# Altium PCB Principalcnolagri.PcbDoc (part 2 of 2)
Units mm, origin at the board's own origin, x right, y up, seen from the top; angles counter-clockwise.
Board outline 45.4 x 70.2 mm, 2 copper layers (Top Layer, Bottom Layer); 50 components, 70 nets, 241 pads, 57 vias.

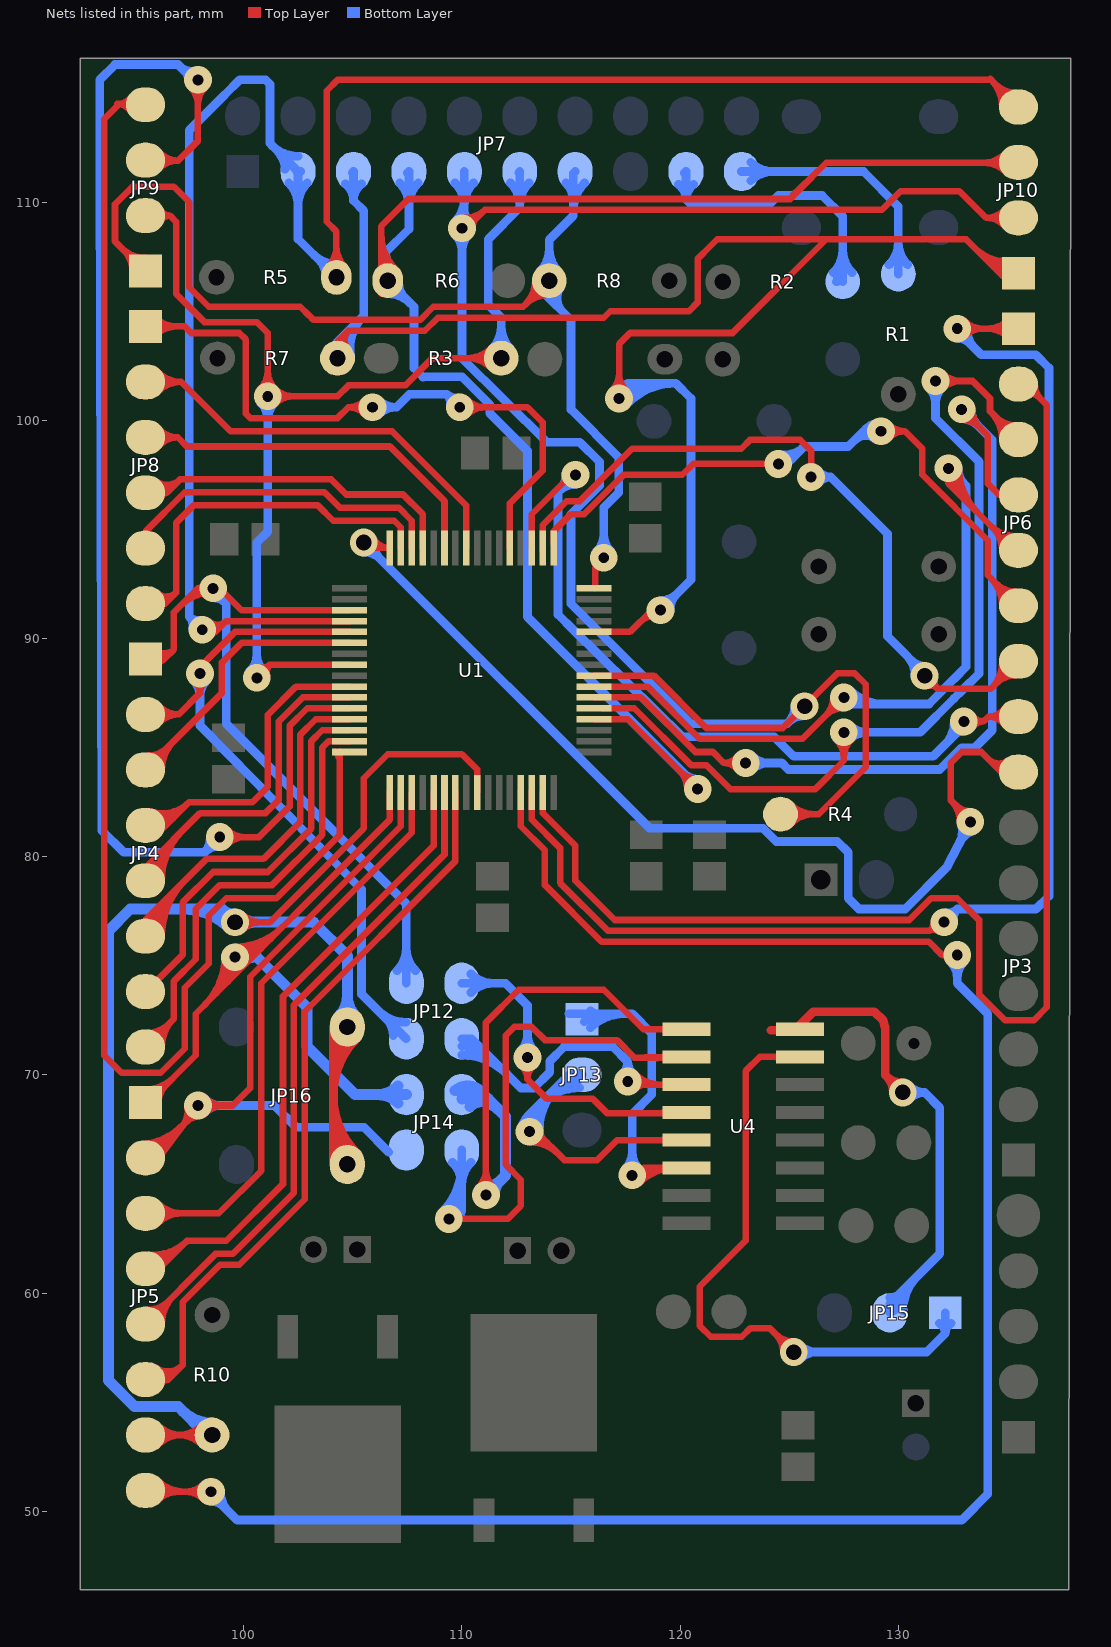
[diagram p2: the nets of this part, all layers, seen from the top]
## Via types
v1: diameter 1.27, hole 0.5, Top Layer to Bottom Layer, 46 vias
v2: diameter 1.27, hole 0.711, Top Layer to Bottom Layer, 10 vias
v3: diameter 1.524, hole 0.5, Top Layer to Bottom Layer, 1 vias

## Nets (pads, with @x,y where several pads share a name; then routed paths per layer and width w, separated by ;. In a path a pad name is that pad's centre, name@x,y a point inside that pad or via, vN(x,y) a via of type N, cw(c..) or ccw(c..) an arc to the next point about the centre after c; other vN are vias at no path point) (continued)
NetJP3_8: JP3.8 U1.16 | length 55.6
  Top Layer w0.3: v2(105.5,94.4) 105.1,94.6 105.55,94.15 U1.16@106.7,94.15 cw(c106.7,95.012) v2@105.932,94.62 ; v2@105.665,94.484 ccw(c106.21,94.762) 106.21,94.15 ; 132.401,82.599 cw(c131.403,81.6) v1@132.815,81.6 ; 132.643,82.357 ccw(c133.3,83.014) v1@133.3,82.085 ; v1(133.3,81.6) 133.3,81.7 132.4,82.6 132.4,84.3 132.9,84.8 133.8,84.8 134.72,83.88 JP3.8@135.5,83.88 ; 134.14,84.46 ccw(c134.609,84.929) JP3.8@135.009,84.399 ; 134.384,84.216 ccw(c134.819,84.651) JP3.8@135.189,84.16
  Bottom Layer w0.4: v2@105.5,93.965 cw(c105.5,92.915) 106.243,93.657 cw(c106.985,94.4) v2@105.935,94.4 ; v2(105.5,94.4) 118.6,81.3 123.8,81.3 124.4,80.7 127.2,80.7 127.7,80.2 127.7,78.1 128.2,77.6 130.3,77.6 132.2,79.5 v1(133.3,81.6) ; v1@132.885,81.47 cw(c131.882,81.157) 132.813,80.67 cw(c133.743,80.182) v1@133.43,81.185
NetJP4_1: JP4.1 JP12.1 U1.19 | length 46.5
  Top Layer w0.3: JP4.1@95.5,89.4 JP4.1@95.5,89.06 ; JP4.1@95.708,89.276 ccw(c96.142,89.726) 96.584,89.284 ; JP4.1@95.916,89.492 ccw(c96.354,89.946) 96.8,89.5 ; JP4.1@96.063,88.853 cw(c96.36,88.744) 96.36,89.06 ; JP4.1@96.063,89.267 ccw(c96.36,89.376) 96.36,89.06 ; 96.368,89.068 cw(c95.93,89.506) JP4.1@95.5,89.06 ; 97.089,91.489 cw(c98.6,89.978) v1@98.6,92.115 ; 97.55,91.95 cw(c97.907,91.593) v1@98.261,91.954 ; 97.601,92.001 cw(c98.6,91.003) v1@98.6,92.415 ; 97.764,92.164 cw(c98.119,91.809) v1@98.471,92.168 ; v1@98.146,92.13 ccw(c97.9,92.037) 97.9,92.3 ; v1@98.146,92.47 cw(c97.9,92.563) 97.9,92.3 ; v1@98.8,92 v1(98.6,92.3) 97.9,92.3 ; v1@98.9,92.3 99.9,91.3 U1.19@104.85,91.3 ; JP4.1@95.5,89.06 96.36,89.06 ; 96.36,89.06 96.8,89.5 ; 96.8,89.5 96.8,91.2 97.9,92.3
  Bottom Layer w0.4: v1(98.6,92.3) 99.2,91.6 ; v1@98.609,91.865 cw(c98.623,91.106) 99.2,91.6 ; v1@99.028,92.225 ccw(c99.777,92.094) 99.2,91.6 ; JP12.1@107.026,74.774 ccw(c106.001,75.799) 107.45,75.799 ccw(c108.899,75.799) JP12.1@107.874,74.774 ; JP12.1@107.45,74.2 107.45,77.85 99.2,86.1 99.2,91.6
NetJP4_2: JP4.2 JP12.3 U1.21 | length 39.9
  Top Layer w0.3: JP4.2@95.5,87 JP4.2@95.5,86.52 97.02,86.52 ; JP4.2@96.092,86.095 cw(c97.02,85.294) 97.02,86.52 ; JP4.2@96.092,86.945 ccw(c97.02,87.746) 97.02,86.52 ; v1@97.733,87.995 cw(c97.408,87.5) 98,87.5 ; v1@98.267,87.995 ccw(c98.592,87.5) 98,87.5 ; U1.21@104.85,90.3 99.6,90.3 98,88.7 98,87.5 ; 97.02,86.52 98,87.5
  Bottom Layer w0.4: v1@97.692,88.092 cw(c96.95,87.35) 98,87.35 cw(c99.05,87.35) v1@98.308,88.092 ; v1(98,88.4) 98,86 105.4,78.5 105.4,73.7 105.41,73.7 JP12.3@107.45,71.66 ; 106.17,72.94 ccw(c107.45,74.221) JP12.3@107.45,72.41 ; 106.532,72.578 cw(c105.764,71.81) JP12.3@106.85,71.81
NetJP4_3: JP4.3 U1.22 | length 16.3
  Top Layer w0.3: JP4.3@95.6,84.63 ccw(c95.6,85.91) 96.505,85.005 ; JP4.3@95.88,83.98 JP4.3@95.5,83.98 95.5,84 99,87.5 99,88.9 99.9,89.8 U1.22@104.85,89.8 ; JP4.3@95.95,83.98 cw(c97.085,83.98) 96.282,84.782 ; JP4.3@96.25,83.98 cw(c98.109,83.98) 96.794,85.294
NetJP4_4: JP4.4 U1.26 | length 20.2
  Top Layer w0.3: JP4.4@95.5,81.44 96.44,81.44 ; JP4.4@95.529,81.2 ccw(c95.787,82.072) 96.429,81.429 ; JP4.4@95.614,81.488 ccw(c95.949,82.623) 96.786,81.786 ; JP4.4@95.699,81.776 ccw(c96.112,83.174) 97.143,82.143 ; JP4.4@95.784,82.063 ccw(c96.275,83.725) 97.5,82.5 ; JP4.4@96.229,81.277 cw(c96.44,81.222) 96.44,81.44 ; JP4.4@96.229,81.603 ccw(c96.44,81.658) 96.44,81.44 ; U1.26@104.85,87.8 102.4,87.8 101.1,86.5 101.1,83.2 100.4,82.5 97.5,82.5 ; 96.44,81.44 97.5,82.5
NetJP4_5: JP4.5 U1.27 | length 21.5
  Top Layer w0.3: JP4.5@95.65,78.9 cw(c97.461,78.9) 96.18,80.18 ; JP4.5@95.7,78.9 JP4.5@95.5,78.9 95.5,79.5 98,82 101,82 101.6,82.6 101.6,86.2 102.7,87.3 U1.27@104.85,87.3 ; JP4.5@95.95,78.9 cw(c98.485,78.9) 96.692,80.692 ; JP4.5@96.25,78.9 cw(c99.509,78.9) 97.205,81.205
NetJP4_6: JP4.6 U1.29 | length 24.1
  Top Layer w0.3: JP4.6@95.35,76.36 cw(c96.774,76.36) 95.767,77.367 ; JP4.6@95.5,76.36 95.5,77.1 98.3,79.9 100.9,79.9 102.6,81.6 102.6,85.6 103.3,86.3 U1.29@104.85,86.3 ; JP4.6@95.65,76.36 cw(c97.799,76.36) 96.279,77.879 ; JP4.6@95.95,76.36 cw(c98.823,76.36) 96.791,78.391 ; JP4.6@96.25,76.36 cw(c99.847,76.36) 97.304,78.904
NetJP4_7: JP4.7 U1.30 | length 18.1
  Top Layer w0.3: JP4.7@95.5,73.82 95.52,73.82 97.2,75.5 97.2,77.9 98.6,79.3 101.1,79.3 103.1,81.3 103.1,85.3 103.6,85.8 U1.30@104.85,85.8
NetJP4_8: JP4.8 U1.31 | length 23.2
  Top Layer w0.3: JP4.8@95.5,71.28 96.8,72.58 96.8,74.3 97.8,75.3 97.8,77.6 98.9,78.7 101.3,78.7 103.6,81 103.6,85 103.9,85.3 U1.31@104.85,85.3 ; JP4.8@95.6,71.93 ccw(c95.6,73.258) 96.539,72.319 ; JP4.8@95.95,71.28 cw(c97.036,71.28) 96.268,72.048 ; JP4.8@96.25,71.28 cw(c98.061,71.28) 96.78,72.56
NetJP5_1: JP5.1 JP14.1 U1.33 | length 49.9
  Top Layer w0.3: JP5.1@95.5,68.74 95.64,68.74 97.8,70.9 97.8,72.8 106.686,81.686 106.7,81.686 U1.33@106.7,82.95 ; JP5.1@95.5,69.04 ccw(c95.5,70.102) 96.251,69.351 ; JP5.1@95.5,69.34 ccw(c95.5,71.127) 96.763,69.863 ; JP5.1@96.1,68.74 cw(c97.21,68.74) 96.425,69.525 ; 98.206,73.206 ccw(c96.013,75.4) v1@99.115,75.4 ; 98.718,73.719 ccw(c97.037,75.4) v1@99.415,75.4 ; 99.231,74.231 ccw(c98.061,75.4) v1@99.715,75.4 ; v1@99.6,74.985 ccw(c99.6,75.914) 100.257,75.257 ; v1@99.6,75.285 ccw(c99.6,76.939) 100.769,75.769 ; v1@99.6,75.585 ccw(c99.6,77.963) 101.281,76.282 ; v1@99.6,75.885 ccw(c99.6,78.987) 101.794,76.794 ; 99.743,74.743 ccw(c99.086,75.4) v1@100.015,75.4
  Bottom Layer w0.5: v1@99.6,75.3 v1(99.6,75.4) 100.6,75.4 102.9,73.1 102.9,71.3 105.1,69.1 JP14.1@107.45,69.1 ; v1@99.872,75.128 cw(c100.529,74.471) 100.529,75.4 cw(c100.529,76.329) v1@99.872,75.672 ; JP14.1@107.061,68.711 ccw(c106.122,67.772) 106.122,69.1 ccw(c106.122,70.428) JP14.1@107.061,69.489
NetJP5_2: JP5.2 JP14.3 U1.34 | length 43
  Top Layer w0.3: JP5.2@95.5,66.2 96.1,66.2 v1(97.9,68.6) 99.5,68.6 100.3,69.4 100.3,74.5 107.2,81.4 107.2,82 U1.34@107.2,82.95 U1.34@107.2,83.025 ; JP5.2@95.508,66.843 ccw(c95.093,69.749) 97.441,67.988 ; JP5.2@95.55,66.547 ccw(c95.238,68.735) 97.006,67.409 ; JP5.2@95.593,66.25 ccw(c95.383,67.721) 96.572,66.829 ; v1@97.42,68.531 cw(c96.261,68.366) 97.197,67.663 cw(c98.134,66.961) v1@97.969,68.12 ; v1@98.243,68.257 cw(c99.071,67.429) 99.071,68.6 cw(c99.071,69.771) v1@98.243,68.943
  Bottom Layer w0.4: v1(97.9,68.6) 101.4,68.6 102.4,67.6 105.51,67.6 JP14.3@106.65,66.46 ; v1@98.208,68.292 cw(c98.95,67.55) 98.95,68.6 cw(c98.95,69.65) v1@98.208,68.908
NetJP5_3: JP5.3 U1.35 | length 30.1
  Top Layer w0.3: JP5.3@95.5,63.66 98.86,63.66 100.8,65.6 100.8,74.2 107.7,81.1 U1.35@107.7,82.925 ; JP5.3@95.847,63.413 cw(c96.445,62.815) 96.445,63.66 cw(c96.445,64.505) JP5.3@95.847,63.908 ; JP5.3@96.06,63.2 cw(c97.169,62.091) 97.169,63.66 cw(c97.169,65.229) JP5.3@96.06,64.12
NetJP5_4: JP5.4 U1.37 | length 33
  Top Layer w0.3: JP5.4@95.5,61.12 96.12,61.12 97.4,62.4 ; JP5.4@95.604,61.17 ccw(c95.703,62.281) 96.492,61.492 ; JP5.4@95.631,61.469 ccw(c95.778,63.114) 96.946,61.946 ; JP5.4@95.658,61.767 ccw(c95.852,63.948) 97.4,62.4 ; U1.37@108.7,82.95 108.7,80.5 101.8,73.6 101.8,65 99.2,62.4 97.4,62.4
NetJP5_5: JP5.5 U1.38 | length 35.7
  Top Layer w0.3: JP5.5@95.598,59.23 ccw(c95.594,60.557) 96.535,59.622 ; JP5.5@95.9,58.8 JP5.5@95.5,58.58 ; JP5.5@95.95,58.581 cw(c97.037,58.584) 96.266,59.351 ; JP5.5@96.08,58.58 JP5.5@95.5,58.58 ; JP5.5@96.25,58.582 cw(c98.061,58.588) 96.777,59.865 ; 109.2,82.109 U1.38@109.2,82.95 109.2,80.1 102.3,73.2 102.3,64.6 99.5,61.8 98.7,61.8 JP5.5@95.5,58.58
NetJP5_6: JP5.6 U1.39 | length 38.5
  Top Layer w0.3: JP5.6@95.5,56.04 96.54,56.04 ; JP5.6@95.628,56.082 ccw(c96.094,56.775) 96.684,56.184 ; JP5.6@95.795,56.331 ccw(c96.301,57.083) 96.942,56.442 ; JP5.6@95.962,56.58 ccw(c96.508,57.392) 97.2,56.7 ; JP5.6@96.208,55.811 cw(c96.54,55.685) 96.54,56.04 ; JP5.6@96.208,56.27 ccw(c96.54,56.395) 96.54,56.04 ; U1.39@109.7,82.95 109.7,79.8 102.8,72.9 102.8,64.3 99.8,61.3 98.919,61.3 97.2,59.581 97.2,56.7 ; 96.54,56.04 97.2,56.7
NetJP5_7: JP5.7 JP16.2 R10.2 U1.41 | length 100.7
  Top Layer w0.3: JP5.7@95.8,53.5 R10.2@98.5,53.5 ; JP5.7@95.847,53.253 cw(c96.445,52.655) 96.445,53.5 cw(c96.445,54.345) JP5.7@95.847,53.748 ; JP5.7@96.06,53.04 cw(c97.169,51.931) 97.169,53.5 cw(c97.169,55.069) JP5.7@96.06,53.96 ; R10.2@98.09,53.04 ccw(c96.981,51.931) 96.981,53.5 ccw(c96.981,55.069) R10.2@98.09,53.96 ; R10.2@98.303,53.253 ccw(c97.705,52.655) 97.705,53.5 ccw(c97.705,54.345) R10.2@98.303,53.747 ; v2(99.6,77) 101.2,77 105.5,81.3 105.5,83.6 106.6,84.7 110,84.7 110.7,84 U1.41@110.7,82.95 ; v2@99.943,76.657 cw(c100.771,75.829) 100.771,77 cw(c100.771,78.171) v2@99.943,77.343
  Top Layer w0.4: JP16.2@104.115,65.9 JP16.2@104.115,72.2 ; 104.115,67.05 ccw(c105.8,67.05) JP16.2@104.609,65.859 ; 104.115,68.016 ccw(c106.766,68.016) JP16.2@104.891,66.141 ; 104.115,68.982 ccw(c107.732,68.982) JP16.2@105.174,66.424 ; 104.115,69.118 cw(c107.732,69.118) JP16.2@105.174,71.676 ; 104.115,70.084 cw(c106.766,70.084) JP16.2@104.891,71.959 ; 104.115,71.05 cw(c105.8,71.05) JP16.2@104.609,72.241
  Bottom Layer w0.4: v2(99.6,77) 99.7,77.1 v2(99.6,77)
  Bottom Layer w0.5: 97.184,54.616 ccw(c98.55,55.981) R10.2@98.55,54.05 ; 97.222,77.6 cw(c97.222,74.622) v2@99.328,76.728 ; 97.788,54.012 cw(c97.276,53.5) R10.2@98,53.5 ; 98.429,77.6 cw(c98.429,75.829) v2@99.681,77.081 ; R10.2@98.55,53.5 98.3,53.5 97,54.8 95,54.8 93.8,56 93.8,76.6 94.8,77.6 99,77.6 ; v2@99.216,77.026 ccw(c98.475,77.075) 99,77.6 ; v2@99.574,77.384 cw(c99.525,78.125) 99,77.6 ; v2@99.872,76.728 cw(c100.529,76.071) 100.529,77 cw(c100.529,77.929) v2@99.872,77.272 ; JP16.2@104.361,72.689 ccw(c103.422,73.628) 104.75,73.628 ccw(c106.078,73.628) JP16.2@105.139,72.689 ; JP16.2@104.75,72.2 104.75,75.45 103.2,77 v2(99.6,77) 99,77.6
NetJP5_8: JP5.8 U1.45 | length 98.7
  Top Layer w0.3: JP5.8@95.8,50.9 v1(98.5,50.9) ; JP5.8@95.847,51.208 ccw(c96.59,51.95) 96.59,50.9 ; JP5.8@96.06,50.5 cw(c97.024,49.536) 97.024,50.9 ; JP5.8@96.06,51.42 ccw(c97.314,52.674) 97.314,50.9 ; v1@98.157,50.557 ccw(c97.329,49.729) 97.329,50.9 ccw(c97.329,52.071) v1@98.157,51.243 ; U1.45@112.7,83 112.7,81.4 113.8,80.3 113.8,78.7 116.4,76.1 131.4,76.1 132,75.5 ; v1@132.246,75.33 ccw(c132,75.237) 132,75.5 ; v1@132.246,75.67 cw(c132,75.763) 132,75.5 ; v1(132.7,75.5) 132,75.5
  Bottom Layer w0.4: v1@98.5,50.465 cw(c98.5,49.656) 99.072,50.228 ; v1(98.5,50.9) 98.5,50.8 99.7,49.6 132.9,49.6 134.1,50.8 134.1,72.8 132.7,74.2 v1(132.7,75.5) ; v1@98.935,50.9 ccw(c100.227,50.9) 99.313,49.987 ; v1@132.392,75.192 cw(c131.65,74.45) 132.7,74.45 cw(c133.75,74.45) v1@133.008,75.192
NetJP6_1: JP6.1 U1.46 | length 68.5
  Top Layer w0.3: U1.46@113.2,83 113.2,81.7 114.5,80.4 114.5,78.8 116.7,76.6 131.4,76.6 ; v1@131.615,76.985 cw(c131.188,76.971) 131.4,76.6 ; v1@131.841,76.59 ccw(c131.612,76.229) 131.4,76.6 ; v1(132.1,77) 131.4,76.6 ; v1(132.7,104.2) JP6.1@135.5,104.2 ; v1@133.043,103.857 cw(c133.871,103.029) 133.871,104.2 cw(c133.871,105.371) v1@133.043,104.543 ; JP6.1@135.076,103.776 ccw(c134.051,102.751) 134.051,104.2 ccw(c134.052,105.648) JP6.1@135.076,104.624
  Bottom Layer w0.4: v1(132.1,77) 132.7,77.6 ; v1@132.17,77.429 ccw(c132.269,78.031) 132.7,77.6 ; v1@132.529,77.07 cw(c133.131,77.169) 132.7,77.6 ; v1@132.7,103.765 cw(c132.7,102.956) 133.272,103.528 ; v1(132.7,104.2) 132.7,104.1 133.8,103 136.3,103 136.9,102.4 136.9,78.2 136.3,77.6 132.7,77.6 ; v1@133.135,104.2 ccw(c134.427,104.2) 133.513,103.287
NetJP6_2: JP6.2 U1.47 | length 63
  Top Layer w0.3: U1.47@113.7,82.95 113.7,82 115.2,80.5 115.2,78.9 117,77.1 130.5,77.1 131.5,78.1 132.7,78.1 133.7,77.1 133.7,73.7 134.9,72.5 136.2,72.5 136.8,73.1 136.8,100.7 135.8,101.7 JP6.2@135.5,101.66 ; JP6.2@135.64,101.312 cw(c135.757,100.295) 136.481,101.019 ; JP6.2@136.25,101.66 ccw(c137.24,101.66) 136.54,100.96
NetJP6_3: JP6.3 U1.53 | length 51.6
  Top Layer w0.3: U1.53@116.4,86.8 117.9,86.8 120.5,84.2 121.2,84.2 122.3,83.1 126.2,83.1 127.5,84.4 v1(127.5,85.7) ; v1@127.157,85.357 cw(c126.329,84.529) 127.5,84.529 cw(c128.671,84.529) v1@127.843,85.357 ; v1(131.7,101.8) 133.4,101.8 134.2,101 134.2,100.42 JP6.3@135.5,99.12 ; v1@132.043,101.457 cw(c132.871,100.629) 132.871,101.8 cw(c132.871,102.971) v1@132.043,102.143 ; 134.22,100.4 cw(c132.939,99.12) JP6.3@134.75,99.12 ; 134.461,100.159 ccw(c135.4,101.098) JP6.3@135.4,99.77 ; 134.732,99.888 cw(c133.964,99.12) JP6.3@135.05,99.12
  Bottom Layer w0.4: v1(127.5,85.7) 131,85.7 132.551,87.251 132.951,87.651 133.7,88.4 133.7,98.1 131.7,100.1 v1(131.7,101.8) ; v1@127.808,85.392 cw(c128.55,84.65) 128.55,85.7 cw(c128.55,86.75) v1@127.808,86.008 ; v1@131.392,101.492 cw(c130.65,100.75) 131.7,100.75 cw(c132.75,100.75) v1@132.008,101.492
NetJP6_4: JP6.4 U1.54 | length 48.2
  Top Layer w0.3: U1.54@116.05,87.3 118.2,87.3 120.7,84.8 121.5,84.8 122,84.3 ; v1@122.619,84 ccw(c122,83.512) 122,84.3 ; v1@122.619,84.6 cw(c122,85.088) 122,84.3 ; v1(123,84.3) 122,84.3 ; v1@132.9,100.015 cw(c132.9,98.844) 133.728,99.672 cw(c134.556,100.5) v1@133.385,100.5 ; v1(132.9,100.5) 134.1,99.3 134.1,97.1 134.62,96.58 JP6.4@135.5,96.58 JP6.4@135.5,97.1
  Bottom Layer w0.4: v1(123,84.3) 124.651,84.3 124.951,84 131.9,84 132.9,85 133.5,85 134.3,85.8 134.3,99.1 v1(132.9,100.5) ; v1@123.308,83.992 cw(c124.05,83.25) 124.05,84.3 cw(c124.05,85.35) v1@123.308,84.608 ; v1@132.9,100.065 cw(c132.9,99.015) 133.643,99.757 cw(c134.385,100.5) v1@133.335,100.5
NetJP6_5: JP6.5 U1.55 | length 49.7
  Top Layer w0.3: U1.55@116.05,87.8 118.5,87.8 120.9,85.4 125.6,85.4 v1(127.5,87.3) ; v1@127.015,87.3 cw(c125.844,87.3) 126.672,86.472 cw(c127.5,85.644) v1@127.5,86.815 ; v1@132.185,97.8 ccw(c133.597,97.8) 132.599,96.801 ; v1(132.3,97.8) 132.3,97.1 ; v1@132.485,97.8 ccw(c134.622,97.8) 133.111,96.289 ; v1@132.785,97.8 ccw(c135.646,97.8) 133.623,95.777 ; 134.222,95.178 ccw(c135.4,96.356) JP6.5@135.4,94.69 ; 134.319,95.081 cw(c133.277,94.04) JP6.5@134.75,94.04 ; 134.734,94.666 ccw(c135.4,95.331) JP6.5@135.4,94.39 ; JP6.5@135.5,94.04 135.2,94.2 134.9,94.5 132.3,97.1 ; 132.3,97.1 cw(c132.563,97.1) 132.47,97.346 ccw(c132.563,97.1) 132.3,97.1 ; 132.3,97.1 ccw(c132.037,97.1) 132.13,97.346 cw(c132.037,97.1) 132.3,97.1
  Bottom Layer w0.4: v1(127.5,87.3) 127.8,87 131.4,87 132.406,88.006 132.606,88.206 133.1,88.7 133.1,97 v1(132.3,97.8) ; v1@127.525,87.325 ccw(c128.309,88.109) 128.309,87 ; v1@127.808,87.608 ccw(c129.274,89.074) 129.274,87 ; v1@132.3,97.365 cw(c132.3,96.315) 133.043,97.057 cw(c133.785,97.8) v1@132.735,97.8
NetJP6_6: JP6.6 U1.1 | length 41
  Top Layer w0.3: U1.1@114.2,94.35 114.2,94.9 115,95.7 115.6,95.7 116.8,96.9 ; U1.1@114.2,94.8 cw(c114.441,94.8) 114.271,94.971 ; 116.795,96.905 117.4,97.5 120.1,97.5 120.6,98 v1(124.5,98) ; v1(129.2,99.5) 130.3,99.5 ; v1@129.558,99.173 cw(c130.3,98.495) 130.3,99.5 ; v1@129.558,99.827 ccw(c130.3,100.505) 130.3,99.5 ; 134.22,92.78 cw(c132.939,91.5) JP6.6@134.75,91.5 ; 134.461,92.539 ccw(c135.4,93.478) JP6.6@135.4,92.15 ; 134.732,92.268 cw(c133.964,91.5) JP6.6@135.05,91.5 ; JP6.6@135.5,91.5 134.1,92.9 134.1,94.5 131.1,97.5 131.1,98.7 130.3,99.5
  Bottom Layer w0.4: v1(124.5,98) 124.9,98 125.7,98.8 ; v1@124.505,98.035 ccw(c124.619,98.766) 125.143,98.243 ; v1@124.567,98.43 ccw(c124.769,99.731) 125.7,98.8 ; 127.9,99 cw(c129.042,97.858) v1@129.197,99.465 ; 128,99.1 cw(c128.498,98.602) v1@128.932,99.157 ; 128.32,99.42 cw(c128.779,98.961) v1@129.178,99.472 ; 128.499,99.599 cw(c129.147,98.951) v1@129.235,99.863 ; v1@128.835,99.264 ccw(c128.4,98.982) 128.4,99.5 ; v1@128.835,99.736 cw(c128.4,100.018) 128.4,99.5 ; v1(129.2,99.5) 128.4,99.5 ; 125.7,98.8 127.7,98.8 128.4,99.5
NetJP6_7: JP6.7 U1.2 | length 40.5
  Top Layer w0.3: U1.2@113.7,94 113.7,95.2 114.8,96.3 115.4,96.3 116.29,97.19 117.796,98.696 122.796,98.696 123.2,99.1 125.5,99.1 126,98.6 v1(126,97.4) ; v2(131.2,88.3) 131.8,87.7 ; v2@131.321,87.83 cw(c131.447,87.347) 131.8,87.7 ; v2@131.67,88.179 ccw(c132.153,88.053) 131.8,87.7 ; 134.29,87.75 ccw(c133.175,88.865) JP6.7@134.751,88.932 ; 134.461,87.921 cw(c135.4,86.982) JP6.7@135.4,88.31 ; 134.773,88.233 ccw(c134.101,88.905) JP6.7@135.05,88.945 ; JP6.7@135.5,88.96 134.24,87.7 131.8,87.7
  Bottom Layer w0.4: v1(126,97.4) 126.9,97.4 ; v1@126.341,97.13 cw(c126.9,96.687) 126.9,97.4 ; v1@126.341,97.67 ccw(c126.9,98.113) 126.9,97.4 ; 130.387,89.213 cw(c129.473,88.3) v2@130.765,88.3 ; 130.628,88.972 ccw(c131.2,89.544) v2@131.2,88.735 ; v2(131.2,88.3) 131.2,88.4 129.5,90.1 129.5,94.8 126.9,97.4
NetJP6_8: JP6.8 U1.3 | length 42.1
  Top Layer w0.3: U1.3@113.2,94.15 113.2,95.693 114.807,97.3 v1(115.2,97.5) ; v1(133,86.2) 133.9,86.2 ; v1@133.405,85.933 cw(c133.9,85.608) 133.9,86.2 ; v1@133.405,86.467 ccw(c133.9,86.792) 133.9,86.2 ; JP6.8@134.875,86.037 ccw(c134.12,85.485) 134.12,86.42 ; JP6.8@134.875,86.803 cw(c134.12,87.355) 134.12,86.42 ; JP6.8@135.5,86.42 134.12,86.42 ; 133.9,86.2 134.12,86.42
  Bottom Layer w0.4: v1@114.765,97.5 cw(c113.715,97.5) 114.457,96.757 cw(c115.2,96.015) v1@115.2,97.065 ; v1(115.2,97.5) 114.4,96.7 114.4,91.1 115.1,90.4 120.1,85.5 124.3,85.5 125,84.8 125.2,84.6 131.6,84.6 133.2,86.2 v1(133,86.2) ; 132.116,85.116 ccw(c131.032,86.2) v1@132.565,86.2 ; 132.599,85.599 cw(c133,85.198) v1@133,85.765
NetJP7_3: JP7.3 JP10.4 R5.2 U1.20 | length 102.3
  Top Layer w0.3: v1@98.025,90.313 ccw(c98.368,90.714) 98.741,90.341 ; v1(98.1,90.4) 98.8,90.4 ; v1@98.22,90.541 ccw(c98.579,90.962) 98.97,90.57 ; v1@98.415,90.769 ccw(c98.791,91.209) 99.2,90.8 ; v1@98.554,90.23 cw(c98.8,90.137) 98.8,90.4 ; v1@98.554,90.57 ccw(c98.8,90.663) 98.8,90.4 ; R5.2@103.861,107.039 ccw(c102.922,107.978) 104.25,107.978 ccw(c105.578,107.978) R5.2@104.639,107.039 ; R5.2@104.25,106.55 104.25,108.65 103.8,109.1 103.8,115.1 104.3,115.6 134.26,115.6 JP10.4@135.5,114.36 ; U1.20@104.85,90.8 102.4,90.8 99.2,90.8 ; 134.22,115.64 cw(c132.939,114.36) JP10.4@134.75,114.36 ; 134.461,115.399 ccw(c135.4,116.338) JP10.4@135.4,115.01 ; 134.732,115.128 cw(c133.964,114.36) JP10.4@135.05,114.36 ; 98.8,90.4 99.2,90.8
  Bottom Layer w0.4: v1@97.671,90.47 ccw(c97.069,90.569) 97.5,91 ; v1@98.03,90.829 cw(c97.931,91.431) 97.5,91 ; v1(98.1,90.4) 97.5,91 ; 99.11,114.91 99.086,114.886 99.086,114.873 97.5,113.287 97.5,91 ; 99.117,114.904 99.813,115.6 101,115.6 101.2,115.4 101.2,112.69 102.424,111.466 JP7.3@102.424,111.4 ; 101.295,112.595 ccw(c102.49,113.79) JP7.3@102.49,112.1 ; 101.536,112.354 cw(c100.683,111.5) JP7.3@101.89,111.5 ; JP7.3@102.066,110.876 cw(c101.041,109.851) 102.49,109.851 cw(c103.939,109.851) JP7.3@102.914,110.876 ; JP7.3@102.6,111.4 JP7.3@102.49,111.4 102.49,108.31 R5.2@104.25,106.55 ; 103.226,107.574 ccw(c104.25,108.599) R5.2@104.25,107.15 ; 103.467,107.333 cw(c102.784,106.65) R5.2@103.75,106.65
NetJP7_5: JP7.5 JP10.1 R7.2 U1.60 | length 103.1
  Top Layer w0.3: R7.2@104.25,102.85 R7.2@104.3,102.85 104.3,103.6 104.8,104.1 108.3,104.1 108.9,104.7 116.5,104.7 116.8,105 120.4,105 120.798,105.398 120.798,107.398 121.4,108 121.7,108.3 133.1,108.3 134.66,106.74 JP10.1@135.5,106.74 ; R7.2@104.275,102.875 R7.2@104.3,102.9 ; R7.2@104.337,102.884 cw(c104.751,103.26) 104.355,103.655 ; R7.2@104.559,103.086 cw(c104.983,103.472) 104.578,103.878 ; R7.2@104.781,103.287 cw(c105.216,103.684) 104.8,104.1 ; U1.60@116.05,90.3 117.7,90.3 118.7,91.3 v1(119.1,91.3) ; v1@116.857,101.343 ccw(c116.029,102.171) 117.2,102.171 ccw(c118.371,102.171) v1@117.543,101.343 ; v1(117.2,101) 117.2,103.493 117.707,104 122.4,104 126.7,108.3 ; 118.101,90.701 cw(c119.1,89.703) v1@119.1,91.115 ; 133.52,107.88 ccw(c134.959,109.319) JP10.1@135.377,107.327 ; 133.912,107.488 ccw(c135.095,108.671) JP10.1@135.438,107.034 ; 134.304,107.096 ccw(c135.231,108.023) JP10.1@135.5,106.74 ; 134.696,106.704 ccw(c135.367,107.375) JP10.1@135.562,106.446 ; JP10.1@134.932,106.545 ccw(c134.66,106.452) 134.66,106.74 ccw(c134.66,107.028) JP10.1@134.932,106.935 ; JP10.1@135.46,106.7 JP10.1@135.5,106.74
  Bottom Layer w0.4: R7.2@104.102,102.819 cw(c105.097,102.974) 104.385,103.685 ; R7.2@104.3,102.85 104.3,103.6 105.5,104.8 ; R7.2@104.498,102.881 cw(c106.062,103.123) 104.943,104.243 ; JP7.5@104.661,110.827 cw(c104.069,110.07) 105.03,110.07 ; R7.2@104.893,102.942 cw(c107.027,103.273) 105.5,104.8 ; JP7.5@104.98,111.35 JP7.5@105.03,111.4 105.03,110.07 ; JP7.5@105.399,110.827 ccw(c105.991,110.07) 105.03,110.07 ; v1@116.932,101.248 cw(c117.967,100.289) 117.967,101.7 ; v1(117.2,101) 117.2,101.3 117.6,101.7 ; v1@117.226,100.976 cw(c118.884,99.439) 118.884,101.7 ; v1@117.519,100.704 cw(c119.8,98.59) 119.8,101.7 ; v1@117.558,101.247 cw(c117.852,101.448) 117.6,101.7 ; v1(119.1,91.3) 120.5,92.7 120.5,101 119.8,101.7 ; v1@119.1,91.735 ccw(c119.1,92.785) 119.843,92.043 ccw(c120.585,91.3) v1@119.535,91.3 ; 105.03,110.07 105.5,109.6 105.5,104.8 ; 117.6,101.7 119.8,101.7
NetJP7_7: JP7.7 JP10.3 R6.2 U1.52 | length 92.5
  Top Layer w0.3: 106.3,107.828 ccw(c107.928,107.828) R6.2@106.777,106.677 ; 106.3,108.552 ccw(c108.652,108.552) R6.2@106.989,106.889 ; R6.2@106.4,105.9 106.3,105.8 106.3,108.9 107.542,110.142 125.042,110.142 126,111.1 ; U1.52@116.05,86.3 117.6,86.3 120,83.9 ; v1@120.315,83.112 ccw(c119.239,83.138) 120,83.9 ; v1@120.788,83.585 cw(c120.762,84.661) 120,83.9 ; v1(120.8,83.1) 120,83.9 ; 125.127,110.272 125.99,111.11 126.7,111.8 133.9,111.8 ; 134.591,111.809 ccw(c134.582,112.566) JP10.3@135.141,112.056 ; 134.594,111.809 cw(c134.603,111.052) JP10.3@135.148,111.577 ; JP10.3@134.92,112.258 cw(c133.883,113.203) 133.9,111.8 ; JP10.3@134.932,111.369 ccw(c133.918,110.392) 133.9,111.8 ; JP10.3@135.5,111.82 133.9,111.8
  Bottom Layer w0.4: R6.2@106.246,106.854 ccw(c105.634,107.466) 106.5,107.466 ; R6.2@106.5,106.4 106.5,107.7 ; R6.2@106.6,105.8 cw(c106.6,104.351) 107.624,105.376 ; R6.2@106.6,106.4 107.8,105.2 107.8,102.4 108.219,101.981 110,102 111.272,100.728 111.272,100.328 113,98.6 113,91 120.1,83.9 v1(120.8,83.1) ; R6.2@106.9,106.9 cw(c107.5,107.7) 106.5,107.7 ; R6.2@107.1,106.3 ccw(c108.066,106.3) 107.383,105.617 ; JP7.7@107.146,110.876 cw(c106.121,109.851) 107.57,109.851 cw(c109.019,109.851) JP7.7@107.994,110.876 ; JP7.7@107.5,111.33 JP7.7@107.57,111.4 107.57,108.77 106.5,107.7 ; v1@120.366,83.129 ccw(c119.318,83.199) 120.108,83.89 ccw(c120.899,84.582) v1@120.829,83.534
NetJP7_9: JP7.9 JP10.2 R4.1 U1.56 | length 108.6
  Top Layer w0.3: v1(110,108.8) 110.2,108.8 111.042,109.642 ; v1@110.017,108.984 ccw(c110.084,109.697) 110.591,109.191 ; v1@110.045,109.283 ccw(c110.162,110.521) 111.042,109.642 ; v1@110.485,108.8 cw(c111.173,108.8) 110.687,109.287 ; U1.56@116.05,88.3 118.8,88.3 121.2,85.9 124.7,85.9 v2(125.7,86.9) 127.2,88.4 128,88.4 128.5,87.9 128.5,84.1 126.35,81.95 R4.1@124.6,81.95 ; R4.1@124.847,81.703 cw(c125.445,81.105) 125.445,81.95 cw(c125.445,82.795) R4.1@124.847,82.197 ; R4.1@125.06,81.49 cw(c126.169,80.381) 126.169,81.95 cw(c126.169,83.519) R4.1@125.06,82.41 ; JP10.2@134.899,108.866 ccw(c134.02,108.14) 134.02,109.28 ; JP10.2@134.899,109.694 cw(c134.02,110.42) 134.02,109.28 ; JP10.2@135.5,109.28 134.02,109.28 ; 111.042,109.642 129.242,109.642 129.778,110.178 130.1,110.5 132.8,110.5 134.02,109.28
  Bottom Layer w0.4: v1@109.692,108.492 cw(c108.95,107.75) 110,107.75 cw(c111.05,107.75) v1@110.308,108.492 ; v1@110.1,109.2 110.1,111.39 JP7.9@110.11,111.4 110.11,108.91 v1(110,108.8) 110,102.849 113.9,99 115.4,99 116.3,98.1 116.3,97 115,95.7 115,91.6 120.5,86.1 124.9,86.1 v2(125.7,86.9) ; 110.1,109.609 ccw(c110.809,109.609) 110.308,109.108 cw(c110.785,109.585) 110.11,109.585 ; 110.1,109.827 cw(c111.583,109.827) 110.534,110.876 ccw(c111.559,109.851) 110.11,109.851 ccw(c108.661,109.851) 109.686,110.876 cw(c108.686,109.876) 110.1,109.876 ; 110.1,110.092 cw(c108.708,110.092) 109.692,109.108 ccw(c108.684,110.116) 110.11,110.116 ; v2@125.265,86.9 cw(c124.215,86.9) 124.957,86.157 cw(c125.7,85.415) v2@125.7,86.465
NetJP7_11: JP7.11 JP9.2 R3.1 U1.24 | length 68.6
  Top Layer w0.3: JP9.2@95.5,109.38 96.62,109.38 ; JP9.2@96.189,109.105 cw(c96.62,108.905) 96.62,109.38 ; JP9.2@96.189,109.655 ccw(c96.62,109.855) 96.62,109.38 ; v1(100.6,88.2) 101.2,88.8 ; v1@100.721,88.67 ccw(c100.847,89.153) 101.2,88.8 ; v1@100.757,101.443 ccw(c99.929,102.271) 101.1,102.271 ccw(c102.271,102.271) 101.443,101.443 ccw(c102.271,102.271) 102.271,101.1 ccw(c102.271,99.929) v1@101.443,100.757 ; v1@101.07,88.321 cw(c101.553,88.447) 101.2,88.8 ; U1.24@104.85,88.8 101.2,88.8 ; R3.1@111.34,102.39 ccw(c110.231,101.281) 110.231,102.85 ccw(c110.231,104.419) R3.1@111.34,103.31 ; R3.1@111.553,102.603 ccw(c110.955,102.005) 110.955,102.85 ccw(c110.955,103.695) R3.1@111.553,103.097 ; R3.1@111.8,102.85 108.65,102.85 107.4,101.6 104.8,101.6 104.3,101.1 v1(101.1,101.1) 101.1,104 100.6,104.5 98.2,104.5 96.9,105.8 96.9,109.1 96.62,109.38
  Bottom Layer w0.4: v1@100.292,88.508 ccw(c99.55,89.25) 100.6,89.25 ccw(c101.65,89.25) v1@100.908,88.508 ; v1(100.6,88.2) 100.6,94.4 101.1,94.9 v1(101.1,101.1) ; v1@100.792,100.792 cw(c100.05,100.05) 101.1,100.05 cw(c102.15,100.05) v1@101.408,100.792 ; R3.1@111.376,103.274 ccw(c110.351,104.299) 111.8,104.299 ccw(c113.249,104.299) R3.1@112.224,103.274 ; R3.1@111.8,102.85 111.8,104.7 111.2,105.3 111.2,108.3 112.65,109.75 JP7.11@112.65,111.4 JP7.11@112.6,111.35 ; JP7.11@112.226,110.876 cw(c111.201,109.851) 112.65,109.851 cw(c114.099,109.851) JP7.11@113.074,110.876
NetJP7_13: JP7.13 JP9.1 R8.2 U1.64 | length 65.8
  Top Layer w0.3: 94.407,107.893 ccw(c95.5,108.985) JP9.1@95.5,107.44 ; 94.504,107.796 cw(c93.548,106.84) JP9.1@94.9,106.84 ; JP9.1@94.92,107.38 ccw(c95.5,107.961) JP9.1@95.5,107.14 ; JP9.1@95.5,106.84 95.46,106.84 94.1,108.2 94.1,109.9 94.9,110.7 96.8,110.7 97.5,110 97.5,106.1 98.4,105.2 102.593,105.2 102.996,104.796 ; 103,104.8 103.2,104.6 108.086,104.6 108.686,105.2 112.8,105.2 R8.2@114,106.4 ; R8.2@113.35,106.4 cw(c111.781,106.4) 112.89,105.29 cw(c114,104.181) R8.2@114,105.75 ; R8.2@113.65,106.4 cw(c112.805,106.4) 113.403,105.803 cw(c114,105.205) R8.2@114,106.05 ; U1.64@116.1,92.3 116.1,93.2 ; v1@116.106,93.417 cw(c115.959,93.313) 116.1,93.2 ; v1@116.311,93.253 ccw(c116.241,93.087) 116.1,93.2 ; v1(116.5,93.7) 116.1,93.2
  Bottom Layer w0.4: R8.2@113.576,106.824 ccw(c112.551,107.849) 114,107.849 ccw(c115.449,107.849) R8.2@114.424,106.824 ; R8.2@113.8,105.8 115,104.6 115,100.5 117.192,98.292 117.192,96.692 116.5,96 v1(116.5,93.7) ; R8.2@114,106.4 114,108.276 115.1,109.376 115.1,111.31 JP7.13@115.19,111.4 ; R8.2@114.166,106.288 ccw(c114.785,105.871) 114.257,105.343 ; R8.2@114.497,106.065 ccw(c115.194,105.594) 114.6,105 ; JP7.13@114.766,110.876 cw(c113.959,110.069) 115.1,110.069 ; 115.1,109.634 cw(c116.856,109.634) JP7.13@115.614,110.876 ; v1@116.192,94.008 ccw(c115.45,94.75) 116.5,94.75 ccw(c117.55,94.75) v1@116.808,94.008
NetJP7_17: JP7.17 R2.1 | length 16.4
  Bottom Layer w0.4: JP7.17@119.92,110.813 cw(c119.429,110.13) 120.27,110.13 ; JP7.17@120.204,111.334 JP7.17@120.27,111.4 120.27,110.13 ; JP7.17@120.62,110.813 ccw(c121.111,110.13) 120.27,110.13 ; R2.1@127.026,106.774 ccw(c126.001,107.799) 127.45,107.799 ccw(c128.899,107.799) R2.1@127.874,106.774 ; R2.1@127.15,106.35 127.2,106.35 R2.1@127.2,106.6 ; R2.1@127.45,106.35 127.45,109.35 126.5,110.3 124.5,110.3 124,109.8 120.6,109.8 120.27,110.13
NetJP7_19: JP7.19 R1.1 | length 15.5
  Bottom Layer w0.4: JP7.19@122.81,111.4 128.4,111.4 130,109.8 R1.1@130,106.7 ; JP7.19@123.234,110.976 cw(c124.259,109.951) 124.259,111.4 cw(c124.259,112.849) JP7.19@123.234,111.824 ; R1.1@129.576,107.124 ccw(c128.551,108.149) 130,108.149 ccw(c131.449,108.149) R1.1@130.424,107.124
NetJP8_1: JP8.1 U1.5 | length 37.9
  Top Layer w0.3: JP8.1@95.5,104.3 97.3,104.3 97.6,104 99.8,104 100.1,103.7 100.1,100.3 100.3,100.1 104.3,100.1 104.8,100.6 ; JP8.1@95.924,103.876 cw(c96.948,102.851) 96.948,104.3 cw(c96.948,105.749) JP8.1@95.924,104.724 ; v1@105.542,100.273 ccw(c104.8,99.595) 104.8,100.6 ; v1@105.542,100.927 cw(c104.8,101.605) 104.8,100.6 ; v1(105.9,100.6) 104.8,100.6 ; v1(109.9,100.6) 113,100.6 113.7,99.9 113.7,97.7 112.2,96.2 U1.5@112.2,94.15 ; v1@110.243,100.257 cw(c111.071,99.429) 111.071,100.6 cw(c111.071,101.771) v1@110.243,100.943
  Bottom Layer w0.4: v1(105.9,100.6) 107,100.6 107.6,101.2 109.3,101.2 ; v1@106.208,100.292 cw(c106.95,99.55) 106.95,100.6 cw(c106.95,101.65) v1@106.208,100.908 ; v1@109.471,100.67 ccw(c108.869,100.769) 109.3,101.2 ; v1@109.83,101.029 cw(c109.731,101.631) 109.3,101.2 ; v1(109.9,100.6) 109.3,101.2
NetJP8_2: JP8.2 U1.9 | length 22.7
  Top Layer w0.3: JP8.2@95.5,101.76 97.14,101.76 ; JP8.2@95.851,101.516 cw(c96.429,100.953) 96.429,101.76 cw(c96.429,102.567) JP8.2@95.851,102.004 ; JP8.2@96.066,101.307 cw(c97.14,100.261) 97.14,101.76 ; JP8.2@96.066,102.213 ccw(c97.14,103.259) 97.14,101.76 ; U1.9@110.2,94.15 110.2,96.1 106.8,99.5 99.4,99.5 97.14,101.76
NetJP8_3: JP8.3 U1.11 | length 19
  Top Layer w0.3: JP8.3@95.5,99.22 96.98,99.22 ; JP8.3@96.101,98.806 cw(c96.98,98.08) 96.98,99.22 ; JP8.3@96.101,99.634 ccw(c96.98,100.36) 96.98,99.22 ; U1.11@109.2,94.2 109.2,96.3 106.7,98.8 97.4,98.8 96.98,99.22
NetJP8_4: JP8.4 U1.13 | length 19.3
  Top Layer w0.3: JP8.4@95.5,96.68 96.48,96.68 ; JP8.4@95.629,96.721 ccw(c96.068,97.332) 96.6,96.8 ; JP8.4@95.804,96.964 ccw(c96.277,97.624) 96.85,97.05 ; JP8.4@95.979,97.208 ccw(c96.485,97.915) 97.1,97.3 ; JP8.4@96.221,96.489 cw(c96.48,96.409) 96.48,96.68 ; JP8.4@96.221,96.871 ccw(c96.48,96.951) 96.48,96.68 ; U1.13@108.2,94.15 108.2,95.7 107.3,96.6 104.7,96.6 104,97.3 97.1,97.3 ; 96.48,96.68 97.1,97.3
NetJP8_5: JP8.5 U1.14 | length 15.5
  Top Layer w0.3: JP8.5@95.5,94.14 95.5,94.9 97.3,96.7 103.7,96.7 104.4,96 107.1,96 107.7,95.4 U1.14@107.7,94.15
NetJP8_6: JP8.6 U1.15 | length 19.6
  Top Layer w0.3: JP8.6@95.5,91.6 96.393,91.6 96.9,92.107 ; JP8.6@95.633,91.637 ccw(c96.031,92.08) 96.452,91.659 ; JP8.6@95.834,91.86 ccw(c96.243,92.316) 96.676,91.883 ; JP8.6@96.034,92.084 ccw(c96.455,92.552) 96.9,92.107 ; U1.15@107.2,94.15 107.2,95.1 106.9,95.4 104.1,95.4 103.4,96.1 97.7,96.1 96.9,95.3 96.9,92.107
NetJP9_3: JP9.3 U1.28 | length 70.5
  Top Layer w0.3: JP9.3@95.5,111.92 97,111.9 ; JP9.3@96.09,111.493 cw(c96.984,110.715) 97,111.9 ; JP9.3@96.103,112.332 ccw(c97.016,113.08) 97,111.9 ; v1@97.557,115.257 cw(c96.729,114.429) 97.9,114.429 cw(c99.071,114.429) v1@98.243,115.257 ; v1(97.9,115.6) 97.9,112.8 97,111.9 ; v1(98.9,80.9) 100.7,80.9 102.1,82.3 102.1,85.993 102.907,86.8 U1.28@104.85,86.8 ; v1@99.243,80.557 cw(c100.071,79.729) 100.071,80.9 cw(c100.071,82.071) v1@99.243,81.243
  Bottom Layer w0.4: 93.4,111.6 93.4,115.6 94.1,116.3 97,116.3 v1@98.1,115.2 ; 93.403,111.6 93.5,81.2 94.5,80.2 98.2,80.2 ; 97.1,116.2 ccw(c97.597,116.697) v1@97.784,116.019 ; 97.299,116.001 cw(c96.898,115.6) v1@97.465,115.6 ; v1@98.465,80.881 cw(c97.557,80.843) 98.2,80.2 ; v1@98.881,80.465 ccw(c98.843,79.557) 98.2,80.2 ; v1(98.9,80.9) 98.2,80.2
NetJP9_4: JP9.4 U1.32 | length 69.6
  Top Layer w0.3: JP9.4@94.843,114.125 ccw(c94.174,113.724) 94.2,114.503 ccw(c94.226,115.291) JP9.4@94.869,114.836 ; JP9.4@95.5,114.46 94.3,114.5 93.6,113.8 93.6,70.9 94.4,70.1 96.2,70.1 97.3,71.2 97.3,74 98.4,75.1 98.4,77.3 99.2,78.1 101.5,78.1 104.4,80.993 U1.32@104.4,84.8 ; U1.32@104.2,84.8 cw(c103.717,84.317) 104.4,84.317
NetJP12_2: JP12.2 U4.12 | length 20.6
  Top Layer w0.3: v1@112.7,70.419 cw(c112.212,69.8) 113,69.8 ; v1(113,70.8) 113,69.8 ; v1@113.3,70.419 ccw(c113.788,69.8) 113,69.8 ; 119.017,68.235 ccw(c119.017,68.768) U4.12@119.394,68.391 ; U4.12@120.3,68.285 120.25,68.235 116.665,68.235 116,68.9 113.9,68.9 113,69.8
  Bottom Layer w0.4: JP12.2@109.99,74.2 112,74.2 113,73.2 v1(113,70.8) ; JP12.2@110.414,73.776 cw(c111.439,72.751) 111.439,74.2 cw(c111.439,75.649) JP12.2@110.414,74.624 ; v1@112.692,71.108 ccw(c111.95,71.85) 113,71.85 ccw(c114.05,71.85) v1@113.308,71.108
NetJP12_4: JP12.4 U4.11 | length 21.8
  Top Layer w0.3: v1@117.603,69.702 117.75,69.555 U4.11@120.3,69.555 ; v1@117.731,69.831 ccw(c118.397,70.497) 118.397,69.555 ; v1@117.943,69.357 cw(c118.421,68.879) 118.421,69.555 ; v1@117.943,70.043 ccw(c119.121,71.221) 119.121,69.555 ; U4.11@119.394,69.449 ccw(c119.138,69.193) 119.138,69.555 ccw(c119.138,69.917) U4.11@119.394,69.661
  Bottom Layer w0.4: JP12.4@109.99,70.91 cw(c109.99,68.013) 112.039,70.061 ; JP12.4@109.99,71.31 cw(c109.99,69.379) 111.356,70.744 ; JP12.4@109.99,71.66 110.44,71.66 112.7,69.4 113.3,69.4 114.023,70.123 114.023,70.623 114.7,71.3 116.9,71.3 117.6,70.6 ; v1@117.33,70.041 ccw(c116.887,70.6) 117.6,70.6 ; v1(117.6,69.7) 117.6,70.6 ; v1@117.87,70.041 cw(c118.313,70.6) 117.6,70.6
NetJP13_1: JP13.1 U4.14 | length 23.4
  Top Layer w0.3: v1@117.719,65.481 cw(c118.355,64.845) 118.355,65.745 ; v1(117.8,65.4) 118.055,65.4 118.4,65.745 ; v1@117.931,65.269 cw(c119.08,64.12) 119.08,65.745 ; v1@118.141,65.744 ccw(c118.27,65.875) 118.4,65.745 ; v1@118.143,65.057 cw(c119.804,63.396) U4.14@119.804,65.745 ; v1@118.284,65.434 cw(c118.683,65.462) 118.4,65.745 ; U4.14@119.394,65.639 ccw(c119.138,65.383) 119.138,65.745 ccw(c119.138,66.107) U4.14@119.394,65.851 ; U4.14@120.3,65.745 118.4,65.745
  Bottom Layer w0.4: JP13.1@114.9,72.8 117.8,72.8 118.7,71.9 118.7,69.1 117.8,68.2 v1(117.8,65.4) ; JP13.1@115.606,72.444 cw(c116.466,71.584) 116.466,72.8 ; JP13.1@115.889,72.161 cw(c117.431,70.619) 117.431,72.8 ; JP13.1@115.889,72.939 ccw(c116.224,73.274) JP13.1@116.224,72.8 ; v1@117.492,65.708 ccw(c116.75,66.45) 117.8,66.45 ccw(c118.85,66.45) v1@118.108,65.708
NetJP13_2: JP13.2 U4.13 | length 24.6
  Top Layer w0.3: v1@113.1,66.915 cw(c113.1,65.02) 114.44,66.36 ; v1@113.1,67.215 cw(c113.1,66.044) 113.928,66.872 ; v1(113.1,67.4) 113.4,67.4 114.7,66.1 116.2,66.1 117.115,67.015 U4.13@120.3,67.015 ; v1@113.585,67.4 ccw(c114.032,67.4) 113.716,67.084 ; U4.13@119.394,66.909 ccw(c119.138,66.653) 119.138,67.015 ccw(c119.138,67.377) U4.13@119.394,67.121
  Bottom Layer w0.4: v1@112.735,67.4 cw(c113.785,67.4) 113.043,68.143 ; v1@112.864,67.765 ccw(c112.582,68.2) 113.1,68.2 ; v1(113.1,67.4) 113.1,68.2 ; v1@113.135,67.4 cw(c115.151,67.4) 113.725,68.825 ; v1@113.336,67.765 cw(c113.618,68.2) 113.1,68.2 ; v1@113.535,67.4 cw(c116.517,67.4) 114.408,69.508 ; 113.539,68.639 cw(c115.4,66.779) JP13.2@115.4,69.41 ; 114.222,69.322 cw(c115.4,68.144) JP13.2@115.4,69.81 ; JP13.2@115.5,70.01 114.91,70.01 113.1,68.2
NetJP14_2: JP14.2 U4.9 | length 37.3
  Top Layer w0.3: v1@110.757,64.843 ccw(c109.929,65.671) 111.1,65.671 ccw(c112.271,65.671) v1@111.443,64.843 ; v1(111.1,64.5) 111.1,72.4 112.6,73.9 116.5,73.9 118.305,72.095 U4.9@120.3,72.095 ; U4.9@119.394,71.989 ccw(c119.138,71.733) 119.138,72.095 ccw(c119.138,72.457) U4.9@119.394,72.201
  Bottom Layer w0.5: JP14.2@109.685,69.281 cw(c110.252,68.666) 110.843,69.257 ; JP14.2@109.939,69.397 cw(c110.101,67.975) 111.113,68.987 ; JP14.2@109.99,69.1 111,69.1 ; JP14.2@109.996,68.9 cw(c110.25,66.657) 111.847,68.253 ; JP14.2@110.024,68.913 cw(c110.605,68.282) 111.211,68.889 ; JP14.2@110.362,68.545 cw(c110.958,67.898) 111.58,68.52 ; JP14.2@110.452,68.802 cw(c111,68.448) 111,69.1 ; JP14.2@110.452,69.398 ccw(c111,69.752) 111,69.1 ; v1(111.1,64.5) 112,65.4 112,68.1 111,69.1 ; v1@111.1,64.885 ccw(c111.1,65.814) 111.757,65.157 ccw(c112.414,64.5) v1@111.485,64.5
NetJP14_4: JP14.4 U4.10 | length 33.6
  Top Layer w0.3: v1(109.4,63.4) 112.1,63.4 112.7,64 112.7,65.2 112,65.9 112,71.8 112.4,72.2 113.2,72.2 113.8,71.6 115.7,71.6 116.4,71.6 117.1,71.6 117.9,70.8 118.4,70.788 118.95,70.775 ; 118.4,70.8 120.275,70.8 U4.10@120.3,70.825 ; 119.078,70.8 ccw(c119.078,71.247) U4.10@119.394,70.931 ; 119.198,70.8 cw(c119.198,70.523) U4.10@119.394,70.719
  Bottom Layer w0.4: v1@109.092,63.708 ccw(c106.925,65.875) JP14.4@109.99,65.875 ; v1@109.375,63.425 ccw(c107.891,64.909) 109.99,64.909 ; v1(109.4,63.4) 109.99,63.99 ; v1@109.476,63.828 ccw(c109.578,64.402) 109.99,63.99 ; JP14.4@109.566,65.986 cw(c108.541,64.961) 109.99,64.961 cw(c111.439,64.961) JP14.4@110.414,65.986 ; v1@109.658,63.142 ccw(c108.857,63.943) 109.99,63.943 ; v1@109.828,63.476 cw(c110.402,63.578) 109.99,63.99 ; JP14.4@109.99,66.56 109.99,63.99
NetJP15_1: JP15.1 U4.7 | length 33.9
  Top Layer w0.3: U4.7@124.594,70.719 ccw(c124.338,70.463) 124.338,70.825 ccw(c124.338,71.187) U4.7@124.594,70.931 ; v2@124.715,57.3 ccw(c123.544,57.3) 124.372,58.128 ccw(c125.2,58.956) v2@125.2,57.785 ; v2(125.2,57.3) 124.1,58.4 123.225,58.4 122.825,58 121.4,58 120.9,58.5 120.9,60.3 123,62.4 123,70.175 123.65,70.825 U4.7@125.5,70.825
  Bottom Layer w0.4: v2(125.2,57.3) 131.3,57.3 132.15,58.15 ; v2@125.508,56.992 cw(c126.25,56.25) 126.25,57.3 cw(c126.25,58.35) v2@125.508,57.608 ; JP15.1@131.876,58.623 cw(c131.605,58.15) 132.15,58.15 ; JP15.1@132.15,59.1 132.15,58.15 ; JP15.1@132.424,58.623 ccw(c132.695,58.15) 132.15,58.15
NetJP15_2: JP15.2 U4.8 | length 28.5
  Top Layer w0.4: 124.15,72.045 125.245,72.045 126.1,72.9 128.9,72.9 129.3,72.5 129.383,72.195 129.4,72.133 ; 124.338,72.045 ccw(c124.338,72.457) U4.8@124.629,72.166 ; 129.4,72.2 129.4,70 v2(130.2,69.2) ; v2@129.765,69.2 ccw(c128.715,69.2) 129.457,69.943 ccw(c130.2,70.685) v2@130.2,69.635
  Bottom Layer w0.4: JP15.2@129.61,59.1 129.61,59.51 131.9,61.8 131.9,68.5 131.2,69.2 ; JP15.2@129.61,59.8 ccw(c129.61,60.5) 130.105,60.005 ; JP15.2@129.81,59.2 cw(c131.041,59.2) 130.171,60.071 ; v2(130.2,69.2) 131.2,69.2 ; JP15.2@130.21,59.2 cw(c132.407,59.2) 130.853,60.753 ; v2@130.518,68.903 cw(c131.2,68.268) 131.2,69.2 ; v2@130.518,69.497 ccw(c131.2,70.132) 131.2,69.2
pads on no net: U1.10

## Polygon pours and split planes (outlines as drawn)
GND on Top Layer (hatched 90Degree grid 0.108 track 0.203, remove dead copper): 119.6,98.4 119.6,86.1 131.55,86.1 131.55,98.153 119.6,98.153
NetC4_2 on Top Layer (hatched 90Degree grid 0.208 track 0.203, remove dead copper): 100.002,49.796 108.097,49.796 108.097,64.3 100.002,64.3
NetC1_2 on Top Layer (hatched 90Degree grid 0.208 track 0.203, remove dead copper): 108.5,64.2 116.7,64.2 116.7,49.836 108.5,49.836

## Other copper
Top Layer:
  text "C.I.I.I." at 119,48.3 h1.52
